VERSION 5.7 ;
  NOWIREEXTENSIONATPIN ON ;
  DIVIDERCHAR "/" ;
  BUSBITCHARS "[]" ;
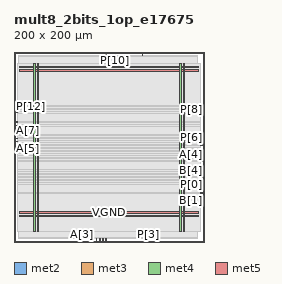
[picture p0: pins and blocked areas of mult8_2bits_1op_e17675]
MACRO mult8_2bits_1op_e17675
  CLASS BLOCK ;
  FOREIGN mult8_2bits_1op_e17675 ;
  ORIGIN 0.000 0.000 ;
  SIZE 200.000 BY 200.000 ;
  PIN A[0]
    DIRECTION INPUT ;
    USE SIGNAL ;
    ANTENNAGATEAREA 0.247500 ;
    PORT
      LAYER met2 ;
        RECT 87.030 0.000 87.310 4.000 ;
    END
  END A[0]
  PIN A[1]
    DIRECTION INPUT ;
    USE SIGNAL ;
    ANTENNAGATEAREA 0.213000 ;
    PORT
      LAYER met2 ;
        RECT 83.810 0.000 84.090 4.000 ;
    END
  END A[1]
  PIN A[2]
    DIRECTION INPUT ;
    USE SIGNAL ;
    ANTENNAGATEAREA 0.495000 ;
    PORT
      LAYER met2 ;
        RECT 67.710 0.000 67.990 4.000 ;
    END
  END A[2]
  PIN A[3]
    DIRECTION INPUT ;
    USE SIGNAL ;
    ANTENNAGATEAREA 0.159000 ;
    PORT
      LAYER met2 ;
        RECT 70.930 0.000 71.210 4.000 ;
    END
  END A[3]
  PIN A[4]
    DIRECTION INPUT ;
    USE SIGNAL ;
    ANTENNAGATEAREA 0.196500 ;
    PORT
      LAYER met3 ;
        RECT 196.000 91.840 200.000 92.440 ;
    END
  END A[4]
  PIN A[5]
    DIRECTION INPUT ;
    USE SIGNAL ;
    ANTENNAGATEAREA 0.213000 ;
    PORT
      LAYER met3 ;
        RECT 0.000 98.640 4.000 99.240 ;
    END
  END A[5]
  PIN A[6]
    DIRECTION INPUT ;
    USE SIGNAL ;
    ANTENNAGATEAREA 0.196500 ;
    PORT
      LAYER met3 ;
        RECT 0.000 112.240 4.000 112.840 ;
    END
  END A[6]
  PIN A[7]
    DIRECTION INPUT ;
    USE SIGNAL ;
    ANTENNAGATEAREA 0.159000 ;
    PORT
      LAYER met3 ;
        RECT 0.000 108.840 4.000 109.440 ;
    END
  END A[7]
  PIN B[0]
    DIRECTION INPUT ;
    USE SIGNAL ;
    ANTENNAGATEAREA 0.213000 ;
    PORT
      LAYER met3 ;
        RECT 196.000 71.440 200.000 72.040 ;
    END
  END B[0]
  PIN B[1]
    DIRECTION INPUT ;
    USE SIGNAL ;
    ANTENNAGATEAREA 0.495000 ;
    PORT
      LAYER met3 ;
        RECT 196.000 51.040 200.000 51.640 ;
    END
  END B[1]
  PIN B[2]
    DIRECTION INPUT ;
    USE SIGNAL ;
    ANTENNAGATEAREA 0.213000 ;
    PORT
      LAYER met2 ;
        RECT 96.690 0.000 96.970 4.000 ;
    END
  END B[2]
  PIN B[3]
    DIRECTION INPUT ;
    USE SIGNAL ;
    ANTENNAGATEAREA 0.213000 ;
    PORT
      LAYER met2 ;
        RECT 90.250 0.000 90.530 4.000 ;
    END
  END B[3]
  PIN B[4]
    DIRECTION INPUT ;
    USE SIGNAL ;
    ANTENNAGATEAREA 0.213000 ;
    PORT
      LAYER met3 ;
        RECT 196.000 74.840 200.000 75.440 ;
    END
  END B[4]
  PIN B[5]
    DIRECTION INPUT ;
    USE SIGNAL ;
    ANTENNAGATEAREA 0.213000 ;
    PORT
      LAYER met3 ;
        RECT 196.000 61.240 200.000 61.840 ;
    END
  END B[5]
  PIN B[6]
    DIRECTION INPUT ;
    USE SIGNAL ;
    ANTENNAGATEAREA 0.213000 ;
    PORT
      LAYER met3 ;
        RECT 0.000 95.240 4.000 95.840 ;
    END
  END B[6]
  PIN B[7]
    DIRECTION INPUT ;
    USE SIGNAL ;
    ANTENNAGATEAREA 0.196500 ;
    PORT
      LAYER met3 ;
        RECT 0.000 105.440 4.000 106.040 ;
    END
  END B[7]
  PIN P[0]
    DIRECTION OUTPUT ;
    USE SIGNAL ;
    ANTENNADIFFAREA 0.445500 ;
    PORT
      LAYER met3 ;
        RECT 196.000 68.040 200.000 68.640 ;
    END
  END P[0]
  PIN P[10]
    DIRECTION OUTPUT ;
    USE SIGNAL ;
    ANTENNADIFFAREA 1.336500 ;
    PORT
      LAYER met2 ;
        RECT 106.350 196.000 106.630 200.000 ;
    END
  END P[10]
  PIN P[11]
    DIRECTION OUTPUT ;
    USE SIGNAL ;
    ANTENNADIFFAREA 1.336500 ;
    PORT
      LAYER met2 ;
        RECT 96.690 196.000 96.970 200.000 ;
    END
  END P[11]
  PIN P[12]
    DIRECTION OUTPUT ;
    USE SIGNAL ;
    ANTENNADIFFAREA 1.336500 ;
    PORT
      LAYER met3 ;
        RECT 0.000 142.840 4.000 143.440 ;
    END
  END P[12]
  PIN P[13]
    DIRECTION OUTPUT ;
    USE SIGNAL ;
    ANTENNADIFFAREA 1.336500 ;
    PORT
      LAYER met3 ;
        RECT 0.000 136.040 4.000 136.640 ;
    END
  END P[13]
  PIN P[14]
    DIRECTION OUTPUT ;
    USE SIGNAL ;
    ANTENNADIFFAREA 1.336500 ;
    PORT
      LAYER met3 ;
        RECT 0.000 125.840 4.000 126.440 ;
    END
  END P[14]
  PIN P[15]
    DIRECTION OUTPUT ;
    USE SIGNAL ;
    ANTENNADIFFAREA 1.336500 ;
    PORT
      LAYER met3 ;
        RECT 0.000 122.440 4.000 123.040 ;
    END
  END P[15]
  PIN P[1]
    DIRECTION OUTPUT ;
    USE SIGNAL ;
    ANTENNADIFFAREA 0.445500 ;
    PORT
      LAYER met2 ;
        RECT 93.470 0.000 93.750 4.000 ;
    END
  END P[1]
  PIN P[2]
    DIRECTION OUTPUT ;
    USE SIGNAL ;
    ANTENNADIFFAREA 0.445500 ;
    PORT
      LAYER met3 ;
        RECT 196.000 64.640 200.000 65.240 ;
    END
  END P[2]
  PIN P[3]
    DIRECTION OUTPUT ;
    USE SIGNAL ;
    ANTENNADIFFAREA 0.445500 ;
    PORT
      LAYER met2 ;
        RECT 141.770 0.000 142.050 4.000 ;
    END
  END P[3]
  PIN P[4]
    DIRECTION OUTPUT ;
    USE SIGNAL ;
    ANTENNADIFFAREA 0.445500 ;
    PORT
      LAYER met3 ;
        RECT 196.000 85.040 200.000 85.640 ;
    END
  END P[4]
  PIN P[5]
    DIRECTION OUTPUT ;
    USE SIGNAL ;
    ANTENNADIFFAREA 0.445500 ;
    PORT
      LAYER met3 ;
        RECT 196.000 88.440 200.000 89.040 ;
    END
  END P[5]
  PIN P[6]
    DIRECTION OUTPUT ;
    USE SIGNAL ;
    ANTENNADIFFAREA 0.445500 ;
    PORT
      LAYER met3 ;
        RECT 196.000 102.040 200.000 102.640 ;
    END
  END P[6]
  PIN P[7]
    DIRECTION OUTPUT ;
    USE SIGNAL ;
    ANTENNADIFFAREA 0.445500 ;
    PORT
      LAYER met3 ;
        RECT 196.000 105.440 200.000 106.040 ;
    END
  END P[7]
  PIN P[8]
    DIRECTION OUTPUT ;
    USE SIGNAL ;
    ANTENNADIFFAREA 1.336500 ;
    PORT
      LAYER met3 ;
        RECT 196.000 139.440 200.000 140.040 ;
    END
  END P[8]
  PIN P[9]
    DIRECTION OUTPUT ;
    USE SIGNAL ;
    ANTENNADIFFAREA 1.336500 ;
    PORT
      LAYER met2 ;
        RECT 135.330 196.000 135.610 200.000 ;
    END
  END P[9]
  PIN VGND
    DIRECTION INOUT ;
    USE GROUND ;
    PORT
      LAYER met4 ;
        RECT 24.340 10.640 25.940 187.920 ;
    END
    PORT
      LAYER met4 ;
        RECT 177.940 10.640 179.540 187.920 ;
    END
    PORT
      LAYER met5 ;
        RECT 5.280 30.030 194.360 31.630 ;
    END
    PORT
      LAYER met5 ;
        RECT 5.280 183.210 194.360 184.810 ;
    END
  END VGND
  PIN VPWR
    DIRECTION INOUT ;
    USE POWER ;
    PORT
      LAYER met4 ;
        RECT 21.040 10.640 22.640 187.920 ;
    END
    PORT
      LAYER met4 ;
        RECT 174.640 10.640 176.240 187.920 ;
    END
    PORT
      LAYER met5 ;
        RECT 5.280 26.730 194.360 28.330 ;
    END
    PORT
      LAYER met5 ;
        RECT 5.280 179.910 194.360 181.510 ;
    END
  END VPWR
  OBS
      LAYER nwell ;
        RECT 5.330 10.795 194.310 187.870 ;
      LAYER li1 ;
        RECT 5.520 10.795 194.120 187.765 ;
      LAYER met1 ;
        RECT 4.210 10.640 194.120 187.920 ;
      LAYER met2 ;
        RECT 4.230 195.720 96.410 196.000 ;
        RECT 97.250 195.720 106.070 196.000 ;
        RECT 106.910 195.720 135.050 196.000 ;
        RECT 135.890 195.720 192.650 196.000 ;
        RECT 4.230 4.280 192.650 195.720 ;
        RECT 4.230 4.000 67.430 4.280 ;
        RECT 68.270 4.000 70.650 4.280 ;
        RECT 71.490 4.000 83.530 4.280 ;
        RECT 84.370 4.000 86.750 4.280 ;
        RECT 87.590 4.000 89.970 4.280 ;
        RECT 90.810 4.000 93.190 4.280 ;
        RECT 94.030 4.000 96.410 4.280 ;
        RECT 97.250 4.000 141.490 4.280 ;
        RECT 142.330 4.000 192.650 4.280 ;
      LAYER met3 ;
        RECT 3.990 143.840 196.000 187.845 ;
        RECT 4.400 142.440 196.000 143.840 ;
        RECT 3.990 140.440 196.000 142.440 ;
        RECT 3.990 139.040 195.600 140.440 ;
        RECT 3.990 137.040 196.000 139.040 ;
        RECT 4.400 135.640 196.000 137.040 ;
        RECT 3.990 126.840 196.000 135.640 ;
        RECT 4.400 125.440 196.000 126.840 ;
        RECT 3.990 123.440 196.000 125.440 ;
        RECT 4.400 122.040 196.000 123.440 ;
        RECT 3.990 113.240 196.000 122.040 ;
        RECT 4.400 111.840 196.000 113.240 ;
        RECT 3.990 109.840 196.000 111.840 ;
        RECT 4.400 108.440 196.000 109.840 ;
        RECT 3.990 106.440 196.000 108.440 ;
        RECT 4.400 105.040 195.600 106.440 ;
        RECT 3.990 103.040 196.000 105.040 ;
        RECT 3.990 101.640 195.600 103.040 ;
        RECT 3.990 99.640 196.000 101.640 ;
        RECT 4.400 98.240 196.000 99.640 ;
        RECT 3.990 96.240 196.000 98.240 ;
        RECT 4.400 94.840 196.000 96.240 ;
        RECT 3.990 92.840 196.000 94.840 ;
        RECT 3.990 91.440 195.600 92.840 ;
        RECT 3.990 89.440 196.000 91.440 ;
        RECT 3.990 88.040 195.600 89.440 ;
        RECT 3.990 86.040 196.000 88.040 ;
        RECT 3.990 84.640 195.600 86.040 ;
        RECT 3.990 75.840 196.000 84.640 ;
        RECT 3.990 74.440 195.600 75.840 ;
        RECT 3.990 72.440 196.000 74.440 ;
        RECT 3.990 71.040 195.600 72.440 ;
        RECT 3.990 69.040 196.000 71.040 ;
        RECT 3.990 67.640 195.600 69.040 ;
        RECT 3.990 65.640 196.000 67.640 ;
        RECT 3.990 64.240 195.600 65.640 ;
        RECT 3.990 62.240 196.000 64.240 ;
        RECT 3.990 60.840 195.600 62.240 ;
        RECT 3.990 52.040 196.000 60.840 ;
        RECT 3.990 50.640 195.600 52.040 ;
        RECT 3.990 10.715 196.000 50.640 ;
  END
END mult8_2bits_1op_e17675
END LIBRARY

